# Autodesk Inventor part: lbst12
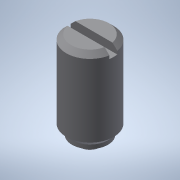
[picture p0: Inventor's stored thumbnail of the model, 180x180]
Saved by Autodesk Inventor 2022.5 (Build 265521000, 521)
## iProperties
Created: 2016-12
Part Number: lbst12
Material: 一般
Document SubType Name: Modeling
Designer: imaocorp
Density: 1 g/cm^3
Appearance: 既定
Author: imaocorp
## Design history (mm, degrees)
node "lbst12.x_t1"
node "lbst12"
node "Base1"
